VERSION 5.7 ;
  NOWIREEXTENSIONATPIN ON ;
  DIVIDERCHAR "/" ;
  BUSBITCHARS "[]" ;
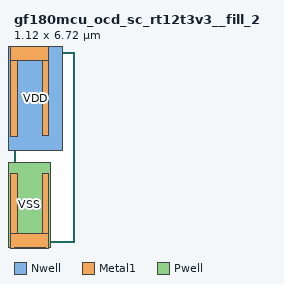
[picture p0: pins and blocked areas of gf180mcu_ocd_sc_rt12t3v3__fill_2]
MACRO gf180mcu_ocd_sc_rt12t3v3__fill_2
  CLASS CORE SPACER ;
  FOREIGN gf180mcu_ocd_sc_rt12t3v3__fill_2 ;
  ORIGIN 0.000 0.000 ;
  SIZE 1.120 BY 6.720 ;
  SYMMETRY X Y ;
  SITE unithd ;
  PIN VDD
    DIRECTION INOUT ;
    USE POWER ;
    SHAPE ABUTMENT ;
    PORT
      LAYER Nwell ;
        RECT -0.610 3.245 1.730 7.330 ;
      LAYER Metal1 ;
        RECT -0.115 6.420 1.235 7.020 ;
        RECT -0.115 3.745 0.115 6.420 ;
        RECT 1.005 3.750 1.235 6.420 ;
    END
  END VDD
  PIN VSS
    DIRECTION INOUT ;
    USE GROUND ;
    SHAPE ABUTMENT ;
    PORT
      LAYER Pwell ;
        RECT -0.180 -0.180 1.300 2.815 ;
        RECT 0.000 -0.300 1.120 -0.180 ;
      LAYER Metal1 ;
        RECT -0.115 0.300 0.115 2.410 ;
        RECT 1.005 0.300 1.235 2.410 ;
        RECT -0.115 -0.300 1.235 0.300 ;
    END
  END VSS
END gf180mcu_ocd_sc_rt12t3v3__fill_2
END LIBRARY

